VERSION 5.7 ;
  NOWIREEXTENSIONATPIN ON ;
  DIVIDERCHAR "/" ;
  BUSBITCHARS "[]" ;
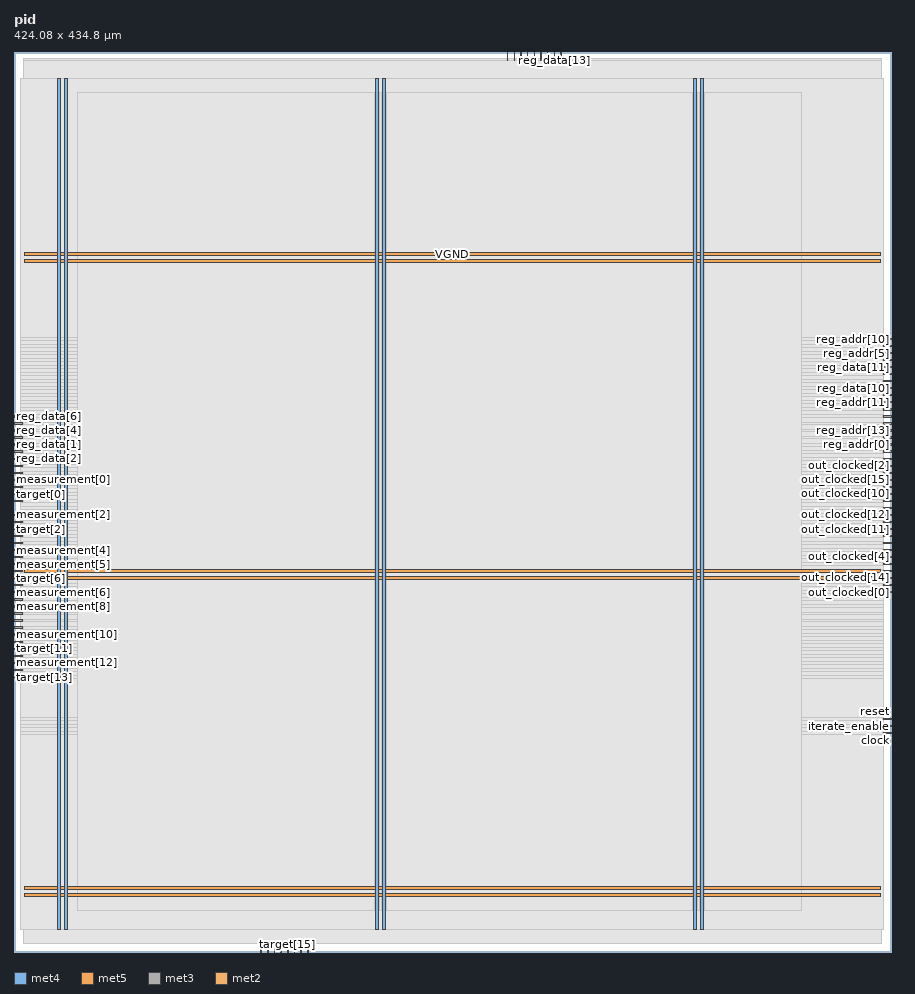
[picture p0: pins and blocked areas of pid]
MACRO pid
  CLASS BLOCK ;
  FOREIGN pid ;
  ORIGIN 0.000 0.000 ;
  SIZE 424.080 BY 434.800 ;
  PIN VGND
    DIRECTION INOUT ;
    USE GROUND ;
    PORT
      LAYER met4 ;
        RECT 24.340 10.640 25.940 421.840 ;
    END
    PORT
      LAYER met4 ;
        RECT 177.940 10.640 179.540 421.840 ;
    END
    PORT
      LAYER met4 ;
        RECT 331.540 10.640 333.140 421.840 ;
    END
    PORT
      LAYER met5 ;
        RECT 5.280 30.030 418.380 31.630 ;
    END
    PORT
      LAYER met5 ;
        RECT 5.280 183.210 418.380 184.810 ;
    END
    PORT
      LAYER met5 ;
        RECT 5.280 336.390 418.380 337.990 ;
    END
  END VGND
  PIN VPWR
    DIRECTION INOUT ;
    USE POWER ;
    PORT
      LAYER met4 ;
        RECT 21.040 10.640 22.640 421.840 ;
    END
    PORT
      LAYER met4 ;
        RECT 174.640 10.640 176.240 421.840 ;
    END
    PORT
      LAYER met4 ;
        RECT 328.240 10.640 329.840 421.840 ;
    END
    PORT
      LAYER met5 ;
        RECT 5.280 26.730 418.380 28.330 ;
    END
    PORT
      LAYER met5 ;
        RECT 5.280 179.910 418.380 181.510 ;
    END
    PORT
      LAYER met5 ;
        RECT 5.280 333.090 418.380 334.690 ;
    END
  END VPWR
  PIN clock
    DIRECTION INPUT ;
    USE SIGNAL ;
    ANTENNAGATEAREA 0.852000 ;
    PORT
      LAYER met3 ;
        RECT 420.080 105.440 424.080 106.040 ;
    END
  END clock
  PIN iterate_enable
    DIRECTION INPUT ;
    USE SIGNAL ;
    ANTENNAGATEAREA 0.159000 ;
    PORT
      LAYER met3 ;
        RECT 420.080 108.840 424.080 109.440 ;
    END
  END iterate_enable
  PIN measurement[0]
    DIRECTION INPUT ;
    USE SIGNAL ;
    ANTENNAGATEAREA 0.213000 ;
    PORT
      LAYER met3 ;
        RECT 0.000 227.840 4.000 228.440 ;
    END
  END measurement[0]
  PIN measurement[10]
    DIRECTION INPUT ;
    USE SIGNAL ;
    ANTENNAGATEAREA 0.196500 ;
    PORT
      LAYER met3 ;
        RECT 0.000 153.040 4.000 153.640 ;
    END
  END measurement[10]
  PIN measurement[11]
    DIRECTION INPUT ;
    USE SIGNAL ;
    ANTENNAGATEAREA 0.196500 ;
    PORT
      LAYER met3 ;
        RECT 0.000 149.640 4.000 150.240 ;
    END
  END measurement[11]
  PIN measurement[12]
    DIRECTION INPUT ;
    USE SIGNAL ;
    ANTENNAGATEAREA 0.196500 ;
    PORT
      LAYER met3 ;
        RECT 0.000 139.440 4.000 140.040 ;
    END
  END measurement[12]
  PIN measurement[13]
    DIRECTION INPUT ;
    USE SIGNAL ;
    ANTENNAGATEAREA 0.196500 ;
    PORT
      LAYER met3 ;
        RECT 0.000 132.640 4.000 133.240 ;
    END
  END measurement[13]
  PIN measurement[14]
    DIRECTION INPUT ;
    USE SIGNAL ;
    ANTENNAGATEAREA 0.196500 ;
    PORT
      LAYER met2 ;
        RECT 141.770 0.000 142.050 4.000 ;
    END
  END measurement[14]
  PIN measurement[15]
    DIRECTION INPUT ;
    USE SIGNAL ;
    ANTENNAGATEAREA 0.196500 ;
    PORT
      LAYER met2 ;
        RECT 135.330 0.000 135.610 4.000 ;
    END
  END measurement[15]
  PIN measurement[16]
    DIRECTION INPUT ;
    USE SIGNAL ;
    ANTENNAGATEAREA 0.196500 ;
    PORT
      LAYER met2 ;
        RECT 125.670 0.000 125.950 4.000 ;
    END
  END measurement[16]
  PIN measurement[17]
    DIRECTION INPUT ;
    USE SIGNAL ;
    ANTENNAGATEAREA 0.196500 ;
    PORT
      LAYER met2 ;
        RECT 122.450 0.000 122.730 4.000 ;
    END
  END measurement[17]
  PIN measurement[1]
    DIRECTION INPUT ;
    USE SIGNAL ;
    ANTENNAGATEAREA 0.213000 ;
    PORT
      LAYER met3 ;
        RECT 0.000 217.640 4.000 218.240 ;
    END
  END measurement[1]
  PIN measurement[2]
    DIRECTION INPUT ;
    USE SIGNAL ;
    ANTENNAGATEAREA 0.196500 ;
    PORT
      LAYER met3 ;
        RECT 0.000 210.840 4.000 211.440 ;
    END
  END measurement[2]
  PIN measurement[3]
    DIRECTION INPUT ;
    USE SIGNAL ;
    ANTENNAGATEAREA 0.196500 ;
    PORT
      LAYER met3 ;
        RECT 0.000 200.640 4.000 201.240 ;
    END
  END measurement[3]
  PIN measurement[4]
    DIRECTION INPUT ;
    USE SIGNAL ;
    ANTENNAGATEAREA 0.196500 ;
    PORT
      LAYER met3 ;
        RECT 0.000 193.840 4.000 194.440 ;
    END
  END measurement[4]
  PIN measurement[5]
    DIRECTION INPUT ;
    USE SIGNAL ;
    ANTENNAGATEAREA 0.196500 ;
    PORT
      LAYER met3 ;
        RECT 0.000 187.040 4.000 187.640 ;
    END
  END measurement[5]
  PIN measurement[6]
    DIRECTION INPUT ;
    USE SIGNAL ;
    ANTENNAGATEAREA 0.196500 ;
    PORT
      LAYER met3 ;
        RECT 0.000 173.440 4.000 174.040 ;
    END
  END measurement[6]
  PIN measurement[7]
    DIRECTION INPUT ;
    USE SIGNAL ;
    ANTENNAGATEAREA 0.213000 ;
    PORT
      LAYER met3 ;
        RECT 0.000 176.840 4.000 177.440 ;
    END
  END measurement[7]
  PIN measurement[8]
    DIRECTION INPUT ;
    USE SIGNAL ;
    ANTENNAGATEAREA 0.213000 ;
    PORT
      LAYER met3 ;
        RECT 0.000 170.040 4.000 170.640 ;
    END
  END measurement[8]
  PIN measurement[9]
    DIRECTION INPUT ;
    USE SIGNAL ;
    ANTENNAGATEAREA 0.196500 ;
    PORT
      LAYER met3 ;
        RECT 0.000 163.240 4.000 163.840 ;
    END
  END measurement[9]
  PIN out_clocked[0]
    DIRECTION OUTPUT ;
    USE SIGNAL ;
    ANTENNADIFFAREA 0.795200 ;
    PORT
      LAYER met3 ;
        RECT 420.080 173.440 424.080 174.040 ;
    END
  END out_clocked[0]
  PIN out_clocked[10]
    DIRECTION OUTPUT ;
    USE SIGNAL ;
    ANTENNADIFFAREA 0.795200 ;
    PORT
      LAYER met3 ;
        RECT 420.080 221.040 424.080 221.640 ;
    END
  END out_clocked[10]
  PIN out_clocked[11]
    DIRECTION OUTPUT ;
    USE SIGNAL ;
    ANTENNADIFFAREA 0.795200 ;
    PORT
      LAYER met3 ;
        RECT 420.080 204.040 424.080 204.640 ;
    END
  END out_clocked[11]
  PIN out_clocked[12]
    DIRECTION OUTPUT ;
    USE SIGNAL ;
    ANTENNADIFFAREA 0.795200 ;
    PORT
      LAYER met3 ;
        RECT 420.080 210.840 424.080 211.440 ;
    END
  END out_clocked[12]
  PIN out_clocked[13]
    DIRECTION OUTPUT ;
    USE SIGNAL ;
    ANTENNADIFFAREA 0.795200 ;
    PORT
      LAYER met3 ;
        RECT 420.080 214.240 424.080 214.840 ;
    END
  END out_clocked[13]
  PIN out_clocked[14]
    DIRECTION OUTPUT ;
    USE SIGNAL ;
    ANTENNADIFFAREA 0.445500 ;
    PORT
      LAYER met3 ;
        RECT 420.080 176.840 424.080 177.440 ;
    END
  END out_clocked[14]
  PIN out_clocked[15]
    DIRECTION OUTPUT ;
    USE SIGNAL ;
    ANTENNADIFFAREA 0.445500 ;
    PORT
      LAYER met3 ;
        RECT 420.080 227.840 424.080 228.440 ;
    END
  END out_clocked[15]
  PIN out_clocked[16]
    DIRECTION OUTPUT ;
    USE SIGNAL ;
    ANTENNADIFFAREA 0.795200 ;
    PORT
      LAYER met3 ;
        RECT 420.080 207.440 424.080 208.040 ;
    END
  END out_clocked[16]
  PIN out_clocked[17]
    DIRECTION OUTPUT ;
    USE SIGNAL ;
    ANTENNADIFFAREA 0.795200 ;
    PORT
      LAYER met3 ;
        RECT 420.080 180.240 424.080 180.840 ;
    END
  END out_clocked[17]
  PIN out_clocked[1]
    DIRECTION OUTPUT ;
    USE SIGNAL ;
    ANTENNADIFFAREA 0.445500 ;
    PORT
      LAYER met3 ;
        RECT 420.080 183.640 424.080 184.240 ;
    END
  END out_clocked[1]
  PIN out_clocked[2]
    DIRECTION OUTPUT ;
    USE SIGNAL ;
    ANTENNADIFFAREA 0.445500 ;
    PORT
      LAYER met3 ;
        RECT 420.080 231.240 424.080 231.840 ;
    END
  END out_clocked[2]
  PIN out_clocked[3]
    DIRECTION OUTPUT ;
    USE SIGNAL ;
    ANTENNADIFFAREA 0.795200 ;
    PORT
      LAYER met3 ;
        RECT 420.080 217.640 424.080 218.240 ;
    END
  END out_clocked[3]
  PIN out_clocked[4]
    DIRECTION OUTPUT ;
    USE SIGNAL ;
    ANTENNADIFFAREA 0.445500 ;
    PORT
      LAYER met3 ;
        RECT 420.080 187.040 424.080 187.640 ;
    END
  END out_clocked[4]
  PIN out_clocked[5]
    DIRECTION OUTPUT ;
    USE SIGNAL ;
    ANTENNADIFFAREA 0.445500 ;
    PORT
      LAYER met3 ;
        RECT 420.080 224.440 424.080 225.040 ;
    END
  END out_clocked[5]
  PIN out_clocked[6]
    DIRECTION OUTPUT ;
    USE SIGNAL ;
    ANTENNADIFFAREA 0.445500 ;
    PORT
      LAYER met3 ;
        RECT 420.080 190.440 424.080 191.040 ;
    END
  END out_clocked[6]
  PIN out_clocked[7]
    DIRECTION OUTPUT ;
    USE SIGNAL ;
    ANTENNADIFFAREA 0.445500 ;
    PORT
      LAYER met3 ;
        RECT 420.080 193.840 424.080 194.440 ;
    END
  END out_clocked[7]
  PIN out_clocked[8]
    DIRECTION OUTPUT ;
    USE SIGNAL ;
    ANTENNADIFFAREA 0.445500 ;
    PORT
      LAYER met3 ;
        RECT 420.080 197.240 424.080 197.840 ;
    END
  END out_clocked[8]
  PIN out_clocked[9]
    DIRECTION OUTPUT ;
    USE SIGNAL ;
    ANTENNADIFFAREA 0.795200 ;
    PORT
      LAYER met3 ;
        RECT 420.080 200.640 424.080 201.240 ;
    END
  END out_clocked[9]
  PIN reg_addr[0]
    DIRECTION INPUT ;
    USE SIGNAL ;
    ANTENNAGATEAREA 0.196500 ;
    PORT
      LAYER met3 ;
        RECT 420.080 241.440 424.080 242.040 ;
    END
  END reg_addr[0]
  PIN reg_addr[10]
    DIRECTION INPUT ;
    USE SIGNAL ;
    ANTENNAGATEAREA 0.196500 ;
    PORT
      LAYER met3 ;
        RECT 420.080 295.840 424.080 296.440 ;
    END
  END reg_addr[10]
  PIN reg_addr[11]
    DIRECTION INPUT ;
    USE SIGNAL ;
    ANTENNAGATEAREA 0.196500 ;
    PORT
      LAYER met3 ;
        RECT 420.080 265.240 424.080 265.840 ;
    END
  END reg_addr[11]
  PIN reg_addr[12]
    DIRECTION INPUT ;
    USE SIGNAL ;
    ANTENNAGATEAREA 0.159000 ;
    PORT
      LAYER met2 ;
        RECT 238.370 430.800 238.650 434.800 ;
    END
  END reg_addr[12]
  PIN reg_addr[13]
    DIRECTION INPUT ;
    USE SIGNAL ;
    ANTENNAGATEAREA 0.196500 ;
    PORT
      LAYER met3 ;
        RECT 420.080 248.240 424.080 248.840 ;
    END
  END reg_addr[13]
  PIN reg_addr[14]
    DIRECTION INPUT ;
    USE SIGNAL ;
    ANTENNAGATEAREA 0.196500 ;
    PORT
      LAYER met3 ;
        RECT 420.080 255.040 424.080 255.640 ;
    END
  END reg_addr[14]
  PIN reg_addr[15]
    DIRECTION INPUT ;
    USE SIGNAL ;
    ANTENNAGATEAREA 0.196500 ;
    PORT
      LAYER met3 ;
        RECT 420.080 261.840 424.080 262.440 ;
    END
  END reg_addr[15]
  PIN reg_addr[16]
    DIRECTION INPUT ;
    USE SIGNAL ;
    ANTENNAGATEAREA 0.196500 ;
    PORT
      LAYER met3 ;
        RECT 420.080 244.840 424.080 245.440 ;
    END
  END reg_addr[16]
  PIN reg_addr[17]
    DIRECTION INPUT ;
    USE SIGNAL ;
    ANTENNAGATEAREA 0.196500 ;
    PORT
      LAYER met3 ;
        RECT 420.080 238.040 424.080 238.640 ;
    END
  END reg_addr[17]
  PIN reg_addr[1]
    DIRECTION INPUT ;
    USE SIGNAL ;
    ANTENNAGATEAREA 0.196500 ;
    PORT
      LAYER met3 ;
        RECT 420.080 258.440 424.080 259.040 ;
    END
  END reg_addr[1]
  PIN reg_addr[2]
    DIRECTION INPUT ;
    USE SIGNAL ;
    ANTENNAGATEAREA 0.196500 ;
    PORT
      LAYER met3 ;
        RECT 420.080 268.640 424.080 269.240 ;
    END
  END reg_addr[2]
  PIN reg_addr[3]
    DIRECTION INPUT ;
    USE SIGNAL ;
    ANTENNAGATEAREA 0.196500 ;
    PORT
      LAYER met3 ;
        RECT 420.080 251.640 424.080 252.240 ;
    END
  END reg_addr[3]
  PIN reg_addr[4]
    DIRECTION INPUT ;
    USE SIGNAL ;
    ANTENNAGATEAREA 0.159000 ;
    PORT
      LAYER met2 ;
        RECT 241.590 430.800 241.870 434.800 ;
    END
  END reg_addr[4]
  PIN reg_addr[5]
    DIRECTION INPUT ;
    USE SIGNAL ;
    ANTENNAGATEAREA 0.196500 ;
    PORT
      LAYER met3 ;
        RECT 420.080 289.040 424.080 289.640 ;
    END
  END reg_addr[5]
  PIN reg_addr[6]
    DIRECTION INPUT ;
    USE SIGNAL ;
    ANTENNAGATEAREA 0.196500 ;
    PORT
      LAYER met3 ;
        RECT 420.080 292.440 424.080 293.040 ;
    END
  END reg_addr[6]
  PIN reg_addr[7]
    DIRECTION INPUT ;
    USE SIGNAL ;
    ANTENNAGATEAREA 0.196500 ;
    PORT
      LAYER met3 ;
        RECT 420.080 285.640 424.080 286.240 ;
    END
  END reg_addr[7]
  PIN reg_addr[8]
    DIRECTION INPUT ;
    USE SIGNAL ;
    ANTENNAGATEAREA 0.196500 ;
    PORT
      LAYER met3 ;
        RECT 420.080 275.440 424.080 276.040 ;
    END
  END reg_addr[8]
  PIN reg_addr[9]
    DIRECTION INPUT ;
    USE SIGNAL ;
    ANTENNAGATEAREA 0.196500 ;
    PORT
      LAYER met3 ;
        RECT 420.080 278.840 424.080 279.440 ;
    END
  END reg_addr[9]
  PIN reg_data[0]
    DIRECTION INPUT ;
    USE SIGNAL ;
    ANTENNAGATEAREA 0.159000 ;
    PORT
      LAYER met3 ;
        RECT 0.000 258.440 4.000 259.040 ;
    END
  END reg_data[0]
  PIN reg_data[10]
    DIRECTION INPUT ;
    USE SIGNAL ;
    ANTENNAGATEAREA 0.213000 ;
    PORT
      LAYER met3 ;
        RECT 420.080 272.040 424.080 272.640 ;
    END
  END reg_data[10]
  PIN reg_data[11]
    DIRECTION INPUT ;
    USE SIGNAL ;
    ANTENNAGATEAREA 0.213000 ;
    PORT
      LAYER met3 ;
        RECT 420.080 282.240 424.080 282.840 ;
    END
  END reg_data[11]
  PIN reg_data[12]
    DIRECTION INPUT ;
    USE SIGNAL ;
    ANTENNAGATEAREA 0.213000 ;
    PORT
      LAYER met2 ;
        RECT 264.130 430.800 264.410 434.800 ;
    END
  END reg_data[12]
  PIN reg_data[13]
    DIRECTION INPUT ;
    USE SIGNAL ;
    ANTENNAGATEAREA 0.213000 ;
    PORT
      LAYER met2 ;
        RECT 260.910 430.800 261.190 434.800 ;
    END
  END reg_data[13]
  PIN reg_data[14]
    DIRECTION INPUT ;
    USE SIGNAL ;
    ANTENNAGATEAREA 0.213000 ;
    PORT
      LAYER met2 ;
        RECT 257.690 430.800 257.970 434.800 ;
    END
  END reg_data[14]
  PIN reg_data[15]
    DIRECTION INPUT ;
    USE SIGNAL ;
    ANTENNAGATEAREA 0.213000 ;
    PORT
      LAYER met2 ;
        RECT 254.470 430.800 254.750 434.800 ;
    END
  END reg_data[15]
  PIN reg_data[16]
    DIRECTION INPUT ;
    USE SIGNAL ;
    ANTENNAGATEAREA 0.213000 ;
    PORT
      LAYER met2 ;
        RECT 251.250 430.800 251.530 434.800 ;
    END
  END reg_data[16]
  PIN reg_data[17]
    DIRECTION INPUT ;
    USE SIGNAL ;
    ANTENNAGATEAREA 0.213000 ;
    PORT
      LAYER met2 ;
        RECT 248.030 430.800 248.310 434.800 ;
    END
  END reg_data[17]
  PIN reg_data[1]
    DIRECTION INPUT ;
    USE SIGNAL ;
    ANTENNAGATEAREA 0.159000 ;
    PORT
      LAYER met3 ;
        RECT 0.000 244.840 4.000 245.440 ;
    END
  END reg_data[1]
  PIN reg_data[2]
    DIRECTION INPUT ;
    USE SIGNAL ;
    ANTENNAGATEAREA 0.159000 ;
    PORT
      LAYER met3 ;
        RECT 0.000 241.440 4.000 242.040 ;
    END
  END reg_data[2]
  PIN reg_data[3]
    DIRECTION INPUT ;
    USE SIGNAL ;
    ANTENNAGATEAREA 0.159000 ;
    PORT
      LAYER met3 ;
        RECT 0.000 238.040 4.000 238.640 ;
    END
  END reg_data[3]
  PIN reg_data[4]
    DIRECTION INPUT ;
    USE SIGNAL ;
    ANTENNAGATEAREA 0.159000 ;
    PORT
      LAYER met3 ;
        RECT 0.000 248.240 4.000 248.840 ;
    END
  END reg_data[4]
  PIN reg_data[5]
    DIRECTION INPUT ;
    USE SIGNAL ;
    ANTENNAGATEAREA 0.159000 ;
    PORT
      LAYER met3 ;
        RECT 0.000 251.640 4.000 252.240 ;
    END
  END reg_data[5]
  PIN reg_data[6]
    DIRECTION INPUT ;
    USE SIGNAL ;
    ANTENNAGATEAREA 0.159000 ;
    PORT
      LAYER met3 ;
        RECT 0.000 255.040 4.000 255.640 ;
    END
  END reg_data[6]
  PIN reg_data[7]
    DIRECTION INPUT ;
    USE SIGNAL ;
    ANTENNAGATEAREA 0.159000 ;
    PORT
      LAYER met3 ;
        RECT 0.000 234.640 4.000 235.240 ;
    END
  END reg_data[7]
  PIN reg_data[8]
    DIRECTION INPUT ;
    USE SIGNAL ;
    ANTENNAGATEAREA 0.213000 ;
    PORT
      LAYER met3 ;
        RECT 0.000 231.240 4.000 231.840 ;
    END
  END reg_data[8]
  PIN reg_data[9]
    DIRECTION INPUT ;
    USE SIGNAL ;
    ANTENNAGATEAREA 0.213000 ;
    PORT
      LAYER met2 ;
        RECT 244.810 430.800 245.090 434.800 ;
    END
  END reg_data[9]
  PIN reset
    DIRECTION INPUT ;
    USE SIGNAL ;
    ANTENNAGATEAREA 0.196500 ;
    PORT
      LAYER met3 ;
        RECT 420.080 112.240 424.080 112.840 ;
    END
  END reset
  PIN target[0]
    DIRECTION INPUT ;
    USE SIGNAL ;
    ANTENNAGATEAREA 0.196500 ;
    PORT
      LAYER met3 ;
        RECT 0.000 224.440 4.000 225.040 ;
    END
  END target[0]
  PIN target[10]
    DIRECTION INPUT ;
    USE SIGNAL ;
    ANTENNAGATEAREA 0.196500 ;
    PORT
      LAYER met3 ;
        RECT 0.000 156.440 4.000 157.040 ;
    END
  END target[10]
  PIN target[11]
    DIRECTION INPUT ;
    USE SIGNAL ;
    ANTENNAGATEAREA 0.196500 ;
    PORT
      LAYER met3 ;
        RECT 0.000 146.240 4.000 146.840 ;
    END
  END target[11]
  PIN target[12]
    DIRECTION INPUT ;
    USE SIGNAL ;
    ANTENNAGATEAREA 0.196500 ;
    PORT
      LAYER met3 ;
        RECT 0.000 142.840 4.000 143.440 ;
    END
  END target[12]
  PIN target[13]
    DIRECTION INPUT ;
    USE SIGNAL ;
    ANTENNAGATEAREA 0.196500 ;
    PORT
      LAYER met3 ;
        RECT 0.000 136.040 4.000 136.640 ;
    END
  END target[13]
  PIN target[14]
    DIRECTION INPUT ;
    USE SIGNAL ;
    ANTENNAGATEAREA 0.196500 ;
    PORT
      LAYER met2 ;
        RECT 138.550 0.000 138.830 4.000 ;
    END
  END target[14]
  PIN target[15]
    DIRECTION INPUT ;
    USE SIGNAL ;
    ANTENNAGATEAREA 0.196500 ;
    PORT
      LAYER met2 ;
        RECT 132.110 0.000 132.390 4.000 ;
    END
  END target[15]
  PIN target[16]
    DIRECTION INPUT ;
    USE SIGNAL ;
    ANTENNAGATEAREA 0.196500 ;
    PORT
      LAYER met2 ;
        RECT 128.890 0.000 129.170 4.000 ;
    END
  END target[16]
  PIN target[17]
    DIRECTION INPUT ;
    USE SIGNAL ;
    ANTENNAGATEAREA 0.196500 ;
    PORT
      LAYER met2 ;
        RECT 119.230 0.000 119.510 4.000 ;
    END
  END target[17]
  PIN target[1]
    DIRECTION INPUT ;
    USE SIGNAL ;
    ANTENNAGATEAREA 0.213000 ;
    PORT
      LAYER met3 ;
        RECT 0.000 221.040 4.000 221.640 ;
    END
  END target[1]
  PIN target[2]
    DIRECTION INPUT ;
    USE SIGNAL ;
    ANTENNAGATEAREA 0.196500 ;
    PORT
      LAYER met3 ;
        RECT 0.000 207.440 4.000 208.040 ;
    END
  END target[2]
  PIN target[3]
    DIRECTION INPUT ;
    USE SIGNAL ;
    ANTENNAGATEAREA 0.196500 ;
    PORT
      LAYER met3 ;
        RECT 0.000 204.040 4.000 204.640 ;
    END
  END target[3]
  PIN target[4]
    DIRECTION INPUT ;
    USE SIGNAL ;
    ANTENNAGATEAREA 0.196500 ;
    PORT
      LAYER met3 ;
        RECT 0.000 197.240 4.000 197.840 ;
    END
  END target[4]
  PIN target[5]
    DIRECTION INPUT ;
    USE SIGNAL ;
    ANTENNAGATEAREA 0.196500 ;
    PORT
      LAYER met3 ;
        RECT 0.000 190.440 4.000 191.040 ;
    END
  END target[5]
  PIN target[6]
    DIRECTION INPUT ;
    USE SIGNAL ;
    ANTENNAGATEAREA 0.126000 ;
    PORT
      LAYER met3 ;
        RECT 0.000 180.240 4.000 180.840 ;
    END
  END target[6]
  PIN target[7]
    DIRECTION INPUT ;
    USE SIGNAL ;
    ANTENNAGATEAREA 0.213000 ;
    PORT
      LAYER met3 ;
        RECT 0.000 183.640 4.000 184.240 ;
    END
  END target[7]
  PIN target[8]
    DIRECTION INPUT ;
    USE SIGNAL ;
    ANTENNAGATEAREA 0.213000 ;
    PORT
      LAYER met3 ;
        RECT 0.000 166.640 4.000 167.240 ;
    END
  END target[8]
  PIN target[9]
    DIRECTION INPUT ;
    USE SIGNAL ;
    ANTENNAGATEAREA 0.196500 ;
    PORT
      LAYER met3 ;
        RECT 0.000 159.840 4.000 160.440 ;
    END
  END target[9]
  PIN write_enable
    DIRECTION INPUT ;
    USE SIGNAL ;
    ANTENNAGATEAREA 0.196500 ;
    PORT
      LAYER met3 ;
        RECT 420.080 234.640 424.080 235.240 ;
    END
  END write_enable
  OBS
      LAYER li1 ;
        RECT 5.520 10.795 418.140 421.685 ;
      LAYER met1 ;
        RECT 4.670 10.640 418.990 421.840 ;
      LAYER met2 ;
        RECT 4.690 430.520 238.090 431.530 ;
        RECT 238.930 430.520 241.310 431.530 ;
        RECT 242.150 430.520 244.530 431.530 ;
        RECT 245.370 430.520 247.750 431.530 ;
        RECT 248.590 430.520 250.970 431.530 ;
        RECT 251.810 430.520 254.190 431.530 ;
        RECT 255.030 430.520 257.410 431.530 ;
        RECT 258.250 430.520 260.630 431.530 ;
        RECT 261.470 430.520 263.850 431.530 ;
        RECT 264.690 430.520 418.970 431.530 ;
        RECT 4.690 4.280 418.970 430.520 ;
        RECT 4.690 4.000 118.950 4.280 ;
        RECT 119.790 4.000 122.170 4.280 ;
        RECT 123.010 4.000 125.390 4.280 ;
        RECT 126.230 4.000 128.610 4.280 ;
        RECT 129.450 4.000 131.830 4.280 ;
        RECT 132.670 4.000 135.050 4.280 ;
        RECT 135.890 4.000 138.270 4.280 ;
        RECT 139.110 4.000 141.490 4.280 ;
        RECT 142.330 4.000 418.970 4.280 ;
      LAYER met3 ;
        RECT 3.070 296.840 420.080 421.765 ;
        RECT 3.070 295.440 419.680 296.840 ;
        RECT 3.070 293.440 420.080 295.440 ;
        RECT 3.070 292.040 419.680 293.440 ;
        RECT 3.070 290.040 420.080 292.040 ;
        RECT 3.070 288.640 419.680 290.040 ;
        RECT 3.070 286.640 420.080 288.640 ;
        RECT 3.070 285.240 419.680 286.640 ;
        RECT 3.070 283.240 420.080 285.240 ;
        RECT 3.070 281.840 419.680 283.240 ;
        RECT 3.070 279.840 420.080 281.840 ;
        RECT 3.070 278.440 419.680 279.840 ;
        RECT 3.070 276.440 420.080 278.440 ;
        RECT 3.070 275.040 419.680 276.440 ;
        RECT 3.070 273.040 420.080 275.040 ;
        RECT 3.070 271.640 419.680 273.040 ;
        RECT 3.070 269.640 420.080 271.640 ;
        RECT 3.070 268.240 419.680 269.640 ;
        RECT 3.070 266.240 420.080 268.240 ;
        RECT 3.070 264.840 419.680 266.240 ;
        RECT 3.070 262.840 420.080 264.840 ;
        RECT 3.070 261.440 419.680 262.840 ;
        RECT 3.070 259.440 420.080 261.440 ;
        RECT 4.400 258.040 419.680 259.440 ;
        RECT 3.070 256.040 420.080 258.040 ;
        RECT 4.400 254.640 419.680 256.040 ;
        RECT 3.070 252.640 420.080 254.640 ;
        RECT 4.400 251.240 419.680 252.640 ;
        RECT 3.070 249.240 420.080 251.240 ;
        RECT 4.400 247.840 419.680 249.240 ;
        RECT 3.070 245.840 420.080 247.840 ;
        RECT 4.400 244.440 419.680 245.840 ;
        RECT 3.070 242.440 420.080 244.440 ;
        RECT 4.400 241.040 419.680 242.440 ;
        RECT 3.070 239.040 420.080 241.040 ;
        RECT 4.400 237.640 419.680 239.040 ;
        RECT 3.070 235.640 420.080 237.640 ;
        RECT 4.400 234.240 419.680 235.640 ;
        RECT 3.070 232.240 420.080 234.240 ;
        RECT 4.400 230.840 419.680 232.240 ;
        RECT 3.070 228.840 420.080 230.840 ;
        RECT 4.400 227.440 419.680 228.840 ;
        RECT 3.070 225.440 420.080 227.440 ;
        RECT 4.400 224.040 419.680 225.440 ;
        RECT 3.070 222.040 420.080 224.040 ;
        RECT 4.400 220.640 419.680 222.040 ;
        RECT 3.070 218.640 420.080 220.640 ;
        RECT 4.400 217.240 419.680 218.640 ;
        RECT 3.070 215.240 420.080 217.240 ;
        RECT 3.070 213.840 419.680 215.240 ;
        RECT 3.070 211.840 420.080 213.840 ;
        RECT 4.400 210.440 419.680 211.840 ;
        RECT 3.070 208.440 420.080 210.440 ;
        RECT 4.400 207.040 419.680 208.440 ;
        RECT 3.070 205.040 420.080 207.040 ;
        RECT 4.400 203.640 419.680 205.040 ;
        RECT 3.070 201.640 420.080 203.640 ;
        RECT 4.400 200.240 419.680 201.640 ;
        RECT 3.070 198.240 420.080 200.240 ;
        RECT 4.400 196.840 419.680 198.240 ;
        RECT 3.070 194.840 420.080 196.840 ;
        RECT 4.400 193.440 419.680 194.840 ;
        RECT 3.070 191.440 420.080 193.440 ;
        RECT 4.400 190.040 419.680 191.440 ;
        RECT 3.070 188.040 420.080 190.040 ;
        RECT 4.400 186.640 419.680 188.040 ;
        RECT 3.070 184.640 420.080 186.640 ;
        RECT 4.400 183.240 419.680 184.640 ;
        RECT 3.070 181.240 420.080 183.240 ;
        RECT 4.400 179.840 419.680 181.240 ;
        RECT 3.070 177.840 420.080 179.840 ;
        RECT 4.400 176.440 419.680 177.840 ;
        RECT 3.070 174.440 420.080 176.440 ;
        RECT 4.400 173.040 419.680 174.440 ;
        RECT 3.070 171.040 420.080 173.040 ;
        RECT 4.400 169.640 420.080 171.040 ;
        RECT 3.070 167.640 420.080 169.640 ;
        RECT 4.400 166.240 420.080 167.640 ;
        RECT 3.070 164.240 420.080 166.240 ;
        RECT 4.400 162.840 420.080 164.240 ;
        RECT 3.070 160.840 420.080 162.840 ;
        RECT 4.400 159.440 420.080 160.840 ;
        RECT 3.070 157.440 420.080 159.440 ;
        RECT 4.400 156.040 420.080 157.440 ;
        RECT 3.070 154.040 420.080 156.040 ;
        RECT 4.400 152.640 420.080 154.040 ;
        RECT 3.070 150.640 420.080 152.640 ;
        RECT 4.400 149.240 420.080 150.640 ;
        RECT 3.070 147.240 420.080 149.240 ;
        RECT 4.400 145.840 420.080 147.240 ;
        RECT 3.070 143.840 420.080 145.840 ;
        RECT 4.400 142.440 420.080 143.840 ;
        RECT 3.070 140.440 420.080 142.440 ;
        RECT 4.400 139.040 420.080 140.440 ;
        RECT 3.070 137.040 420.080 139.040 ;
        RECT 4.400 135.640 420.080 137.040 ;
        RECT 3.070 133.640 420.080 135.640 ;
        RECT 4.400 132.240 420.080 133.640 ;
        RECT 3.070 113.240 420.080 132.240 ;
        RECT 3.070 111.840 419.680 113.240 ;
        RECT 3.070 109.840 420.080 111.840 ;
        RECT 3.070 108.440 419.680 109.840 ;
        RECT 3.070 106.440 420.080 108.440 ;
        RECT 3.070 105.040 419.680 106.440 ;
        RECT 3.070 10.715 420.080 105.040 ;
      LAYER met4 ;
        RECT 30.655 19.895 174.240 415.305 ;
        RECT 176.640 19.895 177.540 415.305 ;
        RECT 179.940 19.895 327.840 415.305 ;
        RECT 330.240 19.895 331.140 415.305 ;
        RECT 333.540 19.895 380.585 415.305 ;
  END
END pid
END LIBRARY

